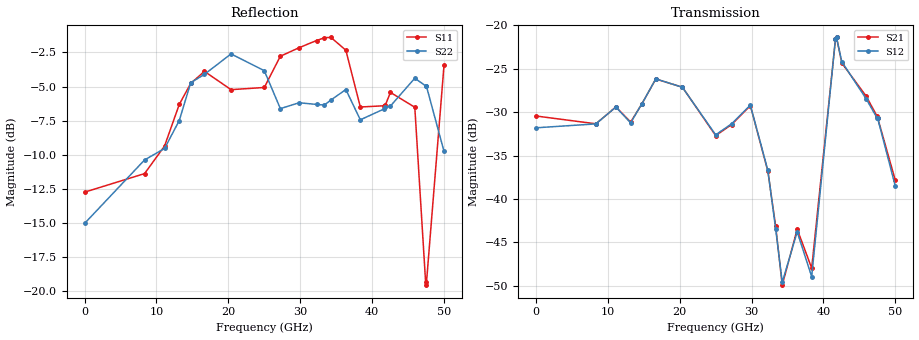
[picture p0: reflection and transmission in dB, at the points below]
!Keysight Technologies,N5245B,MY58422270,A.16.20.02
!Date: Thursday, March 05, 2026 01:42:01
!Correction: S11(C  2-Port  )
!S21(C  2-Port  )
!S12(C  2-Port  )
!S22(C  2-Port  )
!S2P File: Measurements: S11, S21, S12, S22:
# Hz S  dB  R 50
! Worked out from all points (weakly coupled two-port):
!   3201 points, 10 MHz to 50 GHz, reference 50 ohm
!   highest |S21| = -21.37 dB at 41.81 GHz (marker M1); lowest = -49.9 dB at 34.27 GHz (marker M2)
!   lowest |S11| = -19.6 dB at 47.53 GHz (marker M3), VSWR 1.24, Z = 45.8 + j9.24 ohm
!   |S11| at or under -10 dB: start of sweep to 10.03 GHz; 11.36 GHz to 11.93 GHz (576.9 MHz wide, 4.95 % of centre); 46.68 GHz to 48.24 GHz (1.557 GHz wide, 3.28 % of centre)
!   |S22| runs from -18.7 to -2.5 dB; largest |S21 - S12| = 0.009
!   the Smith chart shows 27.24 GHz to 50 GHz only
!   S11 on the Smith chart (normalised r, x): 27.24 GHz: 0.18, +0.36; 32.27 GHz: 0.42, +1.83; 36.35 GHz: 2.44, -3.41; 42.55 GHz: 0.95, -1.24; 47.44 GHz: 0.86, +0.14; 50 GHz: 0.63, -1.39
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1e7  -12.74 -2.5  -30.43 0.2  -31.79 4.1  -15.03 38.6
8.352081e9  -11.38 174.9  -31.33 35.1  -31.34 35.6  -10.38 -173.0
1.113278e10  -9.36 106.6  -29.38 -60.3  -29.40 -60.3  -9.54 84.7
1.317924e10  -6.31 63.1  -31.13 -111.8  -31.22 -111.7  -7.49 -22.4
1.477267e10  -4.77 12.3  -28.99 -144.9  -28.99 -144.8  -4.72 -91.3
1.667854e10  -3.89 -43.9  -26.17 159.3  -26.15 159.4  -4.11 -142.5
2.038092e10  -5.23 -121.1  -27.11 41.8  -27.12 41.5  -2.61 153.7
2.5005e10  -5.07 -178.9  -32.69 -65.2  -32.60 -64.7  -3.84 71.1
2.723893e10  -2.78 139.6  -31.41 -113.6  -31.32 -115.3  -6.62 32.1
2.983216e10  -2.16 94.3  -29.24 159.2  -29.18 159.3  -6.19 -27.9
3.226917e10  -1.63 55.4  -36.80 49.3  -36.71 49.3  -6.31 -104.6
3.334708e10  -1.43 36.0  -43.10 3.9  -43.40 4.7  -6.36 -129.4
3.426877e10  -1.40 19.6  -49.92 -84.1  -49.61 -77.8  -5.99 -149.5
3.634648e10  -2.34 -22.3  -43.48 113.3  -43.78 116.3  -5.22 170.2
3.83617e10  -6.50 -22.3  -47.96 -102.9  -48.94 -5.3  -7.44 137.7
4.167354e10  -6.41 -53.0  -21.56 -54.6  -21.52 -55.5  -6.64 112.5
4.181414e10  -6.39 -53.0  -21.37 -67.8  -21.37 -68.6  -6.52 111.3
4.254837e10  -5.43 -59.9  -24.32 -118.9  -24.17 -119.6  -6.43 107.6
4.593831e10  -6.52 -117.2  -28.14 45.9  -28.45 46.0  -4.39 62.3
4.743801e10  -19.30 130.8  -30.43 -8.2  -30.63 -6.6  -4.95 43.7
4.753174e10  -19.55 108.8  -30.63 -9.3  -30.67 -8.1  -4.93 42.7
5e10  -3.45 -64.6  -37.86 -119.6  -38.53 -140.4  -9.75 7.1
